# Generated by OpenFakeRAM
VERSION 5.7 ;
BUSBITCHARS "[]" ;
PROPERTYDEFINITIONS
  MACRO width INTEGER ;
  MACRO depth INTEGER ;
  MACRO banks INTEGER ;
END PROPERTYDEFINITIONS
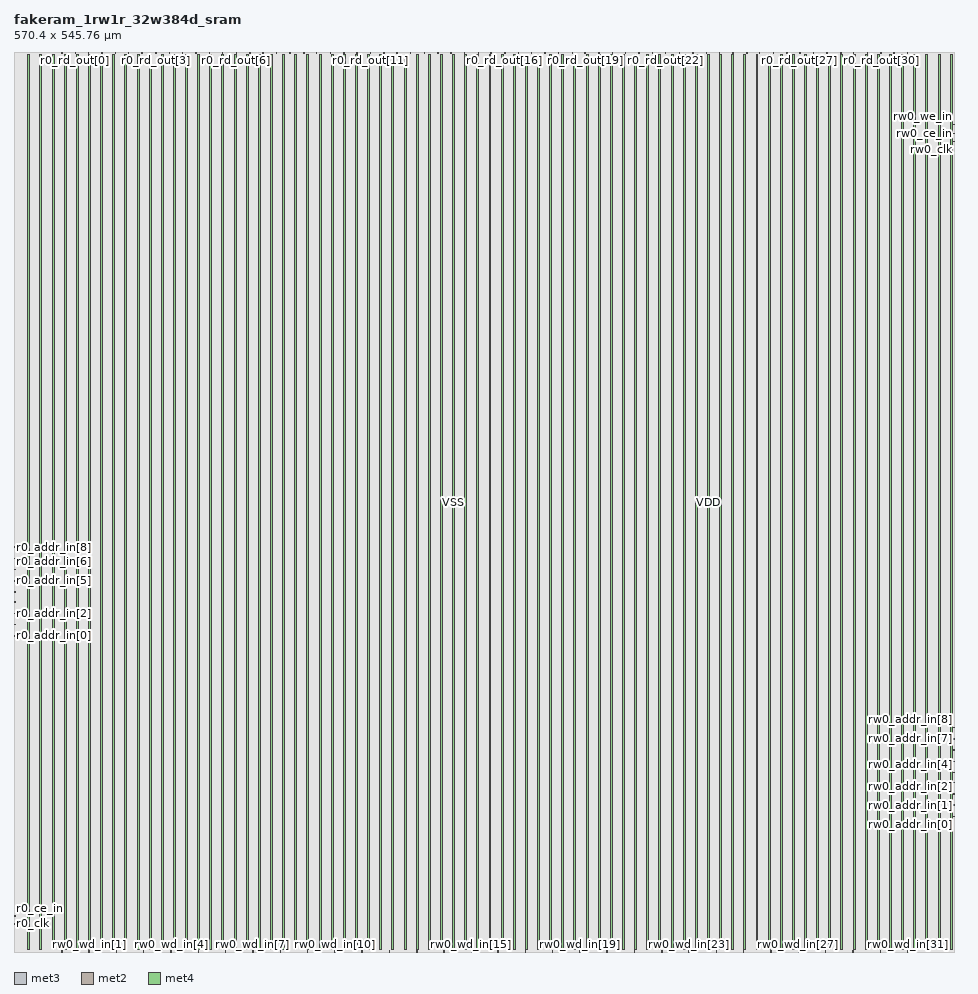
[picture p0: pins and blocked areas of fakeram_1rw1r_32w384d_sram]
MACRO fakeram_1rw1r_32w384d_sram
  PROPERTY width 32 ;
  PROPERTY depth 384 ;
  PROPERTY banks 1 ;
  FOREIGN fakeram_1rw1r_32w384d_sram 0 0 ;
  SYMMETRY X Y R90 ;
  SIZE 570.400 BY 545.760 ;
  CLASS BLOCK ;
  PIN r0_clk
    DIRECTION INPUT ;
    USE SIGNAL ;
    SHAPE ABUTMENT ;
    PORT
      LAYER met3 ;
      RECT 0.000 16.850 0.800 17.150 ;
    END
  END r0_clk
  PIN r0_ce_in
    DIRECTION INPUT ;
    USE SIGNAL ;
    SHAPE ABUTMENT ;
    PORT
      LAYER met3 ;
      RECT 0.000 21.610 0.800 21.910 ;
    END
  END r0_ce_in
  PIN r0_addr_in[0]
    DIRECTION INPUT ;
    USE SIGNAL ;
    SHAPE ABUTMENT ;
    PORT
      LAYER met3 ;
      RECT 0.000 191.610 0.800 191.910 ;
    END
  END r0_addr_in[0]
  PIN r0_addr_in[1]
    DIRECTION INPUT ;
    USE SIGNAL ;
    SHAPE ABUTMENT ;
    PORT
      LAYER met3 ;
      RECT 0.000 198.410 0.800 198.710 ;
    END
  END r0_addr_in[1]
  PIN r0_addr_in[2]
    DIRECTION INPUT ;
    USE SIGNAL ;
    SHAPE ABUTMENT ;
    PORT
      LAYER met3 ;
      RECT 0.000 205.210 0.800 205.510 ;
    END
  END r0_addr_in[2]
  PIN r0_addr_in[3]
    DIRECTION INPUT ;
    USE SIGNAL ;
    SHAPE ABUTMENT ;
    PORT
      LAYER met3 ;
      RECT 0.000 212.010 0.800 212.310 ;
    END
  END r0_addr_in[3]
  PIN r0_addr_in[4]
    DIRECTION INPUT ;
    USE SIGNAL ;
    SHAPE ABUTMENT ;
    PORT
      LAYER met3 ;
      RECT 0.000 218.130 0.800 218.430 ;
    END
  END r0_addr_in[4]
  PIN r0_addr_in[5]
    DIRECTION INPUT ;
    USE SIGNAL ;
    SHAPE ABUTMENT ;
    PORT
      LAYER met3 ;
      RECT 0.000 224.930 0.800 225.230 ;
    END
  END r0_addr_in[5]
  PIN r0_addr_in[6]
    DIRECTION INPUT ;
    USE SIGNAL ;
    SHAPE ABUTMENT ;
    PORT
      LAYER met3 ;
      RECT 0.000 231.730 0.800 232.030 ;
    END
  END r0_addr_in[6]
  PIN r0_addr_in[7]
    DIRECTION INPUT ;
    USE SIGNAL ;
    SHAPE ABUTMENT ;
    PORT
      LAYER met3 ;
      RECT 0.000 238.530 0.800 238.830 ;
    END
  END r0_addr_in[7]
  PIN r0_addr_in[8]
    DIRECTION INPUT ;
    USE SIGNAL ;
    SHAPE ABUTMENT ;
    PORT
      LAYER met3 ;
      RECT 0.000 245.330 0.800 245.630 ;
    END
  END r0_addr_in[8]
  PIN rw0_rd_out[0]
    DIRECTION OUTPUT ;
    USE SIGNAL ;
    SHAPE ABUTMENT ;
    PORT
      LAYER met2 ;
      RECT 28.830 544.960 29.130 545.760 ;
    END
  END rw0_rd_out[0]
  PIN r0_rd_out[0]
    DIRECTION OUTPUT ;
    USE SIGNAL ;
    SHAPE ABUTMENT ;
    PORT
      LAYER met2 ;
      RECT 37.110 544.960 37.410 545.760 ;
    END
  END r0_rd_out[0]
  PIN rw0_rd_out[1]
    DIRECTION OUTPUT ;
    USE SIGNAL ;
    SHAPE ABUTMENT ;
    PORT
      LAYER met2 ;
      RECT 44.930 544.960 45.230 545.760 ;
    END
  END rw0_rd_out[1]
  PIN r0_rd_out[1]
    DIRECTION OUTPUT ;
    USE SIGNAL ;
    SHAPE ABUTMENT ;
    PORT
      LAYER met2 ;
      RECT 53.210 544.960 53.510 545.760 ;
    END
  END r0_rd_out[1]
  PIN rw0_rd_out[2]
    DIRECTION OUTPUT ;
    USE SIGNAL ;
    SHAPE ABUTMENT ;
    PORT
      LAYER met2 ;
      RECT 61.490 544.960 61.790 545.760 ;
    END
  END rw0_rd_out[2]
  PIN r0_rd_out[2]
    DIRECTION OUTPUT ;
    USE SIGNAL ;
    SHAPE ABUTMENT ;
    PORT
      LAYER met2 ;
      RECT 69.310 544.960 69.610 545.760 ;
    END
  END r0_rd_out[2]
  PIN rw0_rd_out[3]
    DIRECTION OUTPUT ;
    USE SIGNAL ;
    SHAPE ABUTMENT ;
    PORT
      LAYER met2 ;
      RECT 77.590 544.960 77.890 545.760 ;
    END
  END rw0_rd_out[3]
  PIN r0_rd_out[3]
    DIRECTION OUTPUT ;
    USE SIGNAL ;
    SHAPE ABUTMENT ;
    PORT
      LAYER met2 ;
      RECT 85.870 544.960 86.170 545.760 ;
    END
  END r0_rd_out[3]
  PIN rw0_rd_out[4]
    DIRECTION OUTPUT ;
    USE SIGNAL ;
    SHAPE ABUTMENT ;
    PORT
      LAYER met2 ;
      RECT 94.150 544.960 94.450 545.760 ;
    END
  END rw0_rd_out[4]
  PIN r0_rd_out[4]
    DIRECTION OUTPUT ;
    USE SIGNAL ;
    SHAPE ABUTMENT ;
    PORT
      LAYER met2 ;
      RECT 101.970 544.960 102.270 545.760 ;
    END
  END r0_rd_out[4]
  PIN rw0_rd_out[5]
    DIRECTION OUTPUT ;
    USE SIGNAL ;
    SHAPE ABUTMENT ;
    PORT
      LAYER met2 ;
      RECT 110.250 544.960 110.550 545.760 ;
    END
  END rw0_rd_out[5]
  PIN r0_rd_out[5]
    DIRECTION OUTPUT ;
    USE SIGNAL ;
    SHAPE ABUTMENT ;
    PORT
      LAYER met2 ;
      RECT 118.530 544.960 118.830 545.760 ;
    END
  END r0_rd_out[5]
  PIN rw0_rd_out[6]
    DIRECTION OUTPUT ;
    USE SIGNAL ;
    SHAPE ABUTMENT ;
    PORT
      LAYER met2 ;
      RECT 126.350 544.960 126.650 545.760 ;
    END
  END rw0_rd_out[6]
  PIN r0_rd_out[6]
    DIRECTION OUTPUT ;
    USE SIGNAL ;
    SHAPE ABUTMENT ;
    PORT
      LAYER met2 ;
      RECT 134.630 544.960 134.930 545.760 ;
    END
  END r0_rd_out[6]
  PIN rw0_rd_out[7]
    DIRECTION OUTPUT ;
    USE SIGNAL ;
    SHAPE ABUTMENT ;
    PORT
      LAYER met2 ;
      RECT 142.910 544.960 143.210 545.760 ;
    END
  END rw0_rd_out[7]
  PIN r0_rd_out[7]
    DIRECTION OUTPUT ;
    USE SIGNAL ;
    SHAPE ABUTMENT ;
    PORT
      LAYER met2 ;
      RECT 150.730 544.960 151.030 545.760 ;
    END
  END r0_rd_out[7]
  PIN rw0_rd_out[8]
    DIRECTION OUTPUT ;
    USE SIGNAL ;
    SHAPE ABUTMENT ;
    PORT
      LAYER met2 ;
      RECT 159.010 544.960 159.310 545.760 ;
    END
  END rw0_rd_out[8]
  PIN r0_rd_out[8]
    DIRECTION OUTPUT ;
    USE SIGNAL ;
    SHAPE ABUTMENT ;
    PORT
      LAYER met2 ;
      RECT 167.290 544.960 167.590 545.760 ;
    END
  END r0_rd_out[8]
  PIN rw0_rd_out[9]
    DIRECTION OUTPUT ;
    USE SIGNAL ;
    SHAPE ABUTMENT ;
    PORT
      LAYER met2 ;
      RECT 175.570 544.960 175.870 545.760 ;
    END
  END rw0_rd_out[9]
  PIN r0_rd_out[9]
    DIRECTION OUTPUT ;
    USE SIGNAL ;
    SHAPE ABUTMENT ;
    PORT
      LAYER met2 ;
      RECT 183.390 544.960 183.690 545.760 ;
    END
  END r0_rd_out[9]
  PIN rw0_rd_out[10]
    DIRECTION OUTPUT ;
    USE SIGNAL ;
    SHAPE ABUTMENT ;
    PORT
      LAYER met2 ;
      RECT 191.670 544.960 191.970 545.760 ;
    END
  END rw0_rd_out[10]
  PIN r0_rd_out[10]
    DIRECTION OUTPUT ;
    USE SIGNAL ;
    SHAPE ABUTMENT ;
    PORT
      LAYER met2 ;
      RECT 199.950 544.960 200.250 545.760 ;
    END
  END r0_rd_out[10]
  PIN rw0_rd_out[11]
    DIRECTION OUTPUT ;
    USE SIGNAL ;
    SHAPE ABUTMENT ;
    PORT
      LAYER met2 ;
      RECT 207.770 544.960 208.070 545.760 ;
    END
  END rw0_rd_out[11]
  PIN r0_rd_out[11]
    DIRECTION OUTPUT ;
    USE SIGNAL ;
    SHAPE ABUTMENT ;
    PORT
      LAYER met2 ;
      RECT 216.050 544.960 216.350 545.760 ;
    END
  END r0_rd_out[11]
  PIN rw0_rd_out[12]
    DIRECTION OUTPUT ;
    USE SIGNAL ;
    SHAPE ABUTMENT ;
    PORT
      LAYER met2 ;
      RECT 224.330 544.960 224.630 545.760 ;
    END
  END rw0_rd_out[12]
  PIN r0_rd_out[12]
    DIRECTION OUTPUT ;
    USE SIGNAL ;
    SHAPE ABUTMENT ;
    PORT
      LAYER met2 ;
      RECT 232.150 544.960 232.450 545.760 ;
    END
  END r0_rd_out[12]
  PIN rw0_rd_out[13]
    DIRECTION OUTPUT ;
    USE SIGNAL ;
    SHAPE ABUTMENT ;
    PORT
      LAYER met2 ;
      RECT 240.430 544.960 240.730 545.760 ;
    END
  END rw0_rd_out[13]
  PIN r0_rd_out[13]
    DIRECTION OUTPUT ;
    USE SIGNAL ;
    SHAPE ABUTMENT ;
    PORT
      LAYER met2 ;
      RECT 248.710 544.960 249.010 545.760 ;
    END
  END r0_rd_out[13]
  PIN rw0_rd_out[14]
    DIRECTION OUTPUT ;
    USE SIGNAL ;
    SHAPE ABUTMENT ;
    PORT
      LAYER met2 ;
      RECT 256.990 544.960 257.290 545.760 ;
    END
  END rw0_rd_out[14]
  PIN r0_rd_out[14]
    DIRECTION OUTPUT ;
    USE SIGNAL ;
    SHAPE ABUTMENT ;
    PORT
      LAYER met2 ;
      RECT 264.810 544.960 265.110 545.760 ;
    END
  END r0_rd_out[14]
  PIN rw0_rd_out[15]
    DIRECTION OUTPUT ;
    USE SIGNAL ;
    SHAPE ABUTMENT ;
    PORT
      LAYER met2 ;
      RECT 273.090 544.960 273.390 545.760 ;
    END
  END rw0_rd_out[15]
  PIN r0_rd_out[15]
    DIRECTION OUTPUT ;
    USE SIGNAL ;
    SHAPE ABUTMENT ;
    PORT
      LAYER met2 ;
      RECT 281.370 544.960 281.670 545.760 ;
    END
  END r0_rd_out[15]
  PIN rw0_rd_out[16]
    DIRECTION OUTPUT ;
    USE SIGNAL ;
    SHAPE ABUTMENT ;
    PORT
      LAYER met2 ;
      RECT 289.190 544.960 289.490 545.760 ;
    END
  END rw0_rd_out[16]
  PIN r0_rd_out[16]
    DIRECTION OUTPUT ;
    USE SIGNAL ;
    SHAPE ABUTMENT ;
    PORT
      LAYER met2 ;
      RECT 297.470 544.960 297.770 545.760 ;
    END
  END r0_rd_out[16]
  PIN rw0_rd_out[17]
    DIRECTION OUTPUT ;
    USE SIGNAL ;
    SHAPE ABUTMENT ;
    PORT
      LAYER met2 ;
      RECT 305.750 544.960 306.050 545.760 ;
    END
  END rw0_rd_out[17]
  PIN r0_rd_out[17]
    DIRECTION OUTPUT ;
    USE SIGNAL ;
    SHAPE ABUTMENT ;
    PORT
      LAYER met2 ;
      RECT 313.570 544.960 313.870 545.760 ;
    END
  END r0_rd_out[17]
  PIN rw0_rd_out[18]
    DIRECTION OUTPUT ;
    USE SIGNAL ;
    SHAPE ABUTMENT ;
    PORT
      LAYER met2 ;
      RECT 321.850 544.960 322.150 545.760 ;
    END
  END rw0_rd_out[18]
  PIN r0_rd_out[18]
    DIRECTION OUTPUT ;
    USE SIGNAL ;
    SHAPE ABUTMENT ;
    PORT
      LAYER met2 ;
      RECT 330.130 544.960 330.430 545.760 ;
    END
  END r0_rd_out[18]
  PIN rw0_rd_out[19]
    DIRECTION OUTPUT ;
    USE SIGNAL ;
    SHAPE ABUTMENT ;
    PORT
      LAYER met2 ;
      RECT 338.410 544.960 338.710 545.760 ;
    END
  END rw0_rd_out[19]
  PIN r0_rd_out[19]
    DIRECTION OUTPUT ;
    USE SIGNAL ;
    SHAPE ABUTMENT ;
    PORT
      LAYER met2 ;
      RECT 346.230 544.960 346.530 545.760 ;
    END
  END r0_rd_out[19]
  PIN rw0_rd_out[20]
    DIRECTION OUTPUT ;
    USE SIGNAL ;
    SHAPE ABUTMENT ;
    PORT
      LAYER met2 ;
      RECT 354.510 544.960 354.810 545.760 ;
    END
  END rw0_rd_out[20]
  PIN r0_rd_out[20]
    DIRECTION OUTPUT ;
    USE SIGNAL ;
    SHAPE ABUTMENT ;
    PORT
      LAYER met2 ;
      RECT 362.790 544.960 363.090 545.760 ;
    END
  END r0_rd_out[20]
  PIN rw0_rd_out[21]
    DIRECTION OUTPUT ;
    USE SIGNAL ;
    SHAPE ABUTMENT ;
    PORT
      LAYER met2 ;
      RECT 370.610 544.960 370.910 545.760 ;
    END
  END rw0_rd_out[21]
  PIN r0_rd_out[21]
    DIRECTION OUTPUT ;
    USE SIGNAL ;
    SHAPE ABUTMENT ;
    PORT
      LAYER met2 ;
      RECT 378.890 544.960 379.190 545.760 ;
    END
  END r0_rd_out[21]
  PIN rw0_rd_out[22]
    DIRECTION OUTPUT ;
    USE SIGNAL ;
    SHAPE ABUTMENT ;
    PORT
      LAYER met2 ;
      RECT 387.170 544.960 387.470 545.760 ;
    END
  END rw0_rd_out[22]
  PIN r0_rd_out[22]
    DIRECTION OUTPUT ;
    USE SIGNAL ;
    SHAPE ABUTMENT ;
    PORT
      LAYER met2 ;
      RECT 394.990 544.960 395.290 545.760 ;
    END
  END r0_rd_out[22]
  PIN rw0_rd_out[23]
    DIRECTION OUTPUT ;
    USE SIGNAL ;
    SHAPE ABUTMENT ;
    PORT
      LAYER met2 ;
      RECT 403.270 544.960 403.570 545.760 ;
    END
  END rw0_rd_out[23]
  PIN r0_rd_out[23]
    DIRECTION OUTPUT ;
    USE SIGNAL ;
    SHAPE ABUTMENT ;
    PORT
      LAYER met2 ;
      RECT 411.550 544.960 411.850 545.760 ;
    END
  END r0_rd_out[23]
  PIN rw0_rd_out[24]
    DIRECTION OUTPUT ;
    USE SIGNAL ;
    SHAPE ABUTMENT ;
    PORT
      LAYER met2 ;
      RECT 419.830 544.960 420.130 545.760 ;
    END
  END rw0_rd_out[24]
  PIN r0_rd_out[24]
    DIRECTION OUTPUT ;
    USE SIGNAL ;
    SHAPE ABUTMENT ;
    PORT
      LAYER met2 ;
      RECT 427.650 544.960 427.950 545.760 ;
    END
  END r0_rd_out[24]
  PIN rw0_rd_out[25]
    DIRECTION OUTPUT ;
    USE SIGNAL ;
    SHAPE ABUTMENT ;
    PORT
      LAYER met2 ;
      RECT 435.930 544.960 436.230 545.760 ;
    END
  END rw0_rd_out[25]
  PIN r0_rd_out[25]
    DIRECTION OUTPUT ;
    USE SIGNAL ;
    SHAPE ABUTMENT ;
    PORT
      LAYER met2 ;
      RECT 444.210 544.960 444.510 545.760 ;
    END
  END r0_rd_out[25]
  PIN rw0_rd_out[26]
    DIRECTION OUTPUT ;
    USE SIGNAL ;
    SHAPE ABUTMENT ;
    PORT
      LAYER met2 ;
      RECT 452.030 544.960 452.330 545.760 ;
    END
  END rw0_rd_out[26]
  PIN r0_rd_out[26]
    DIRECTION OUTPUT ;
    USE SIGNAL ;
    SHAPE ABUTMENT ;
    PORT
      LAYER met2 ;
      RECT 460.310 544.960 460.610 545.760 ;
    END
  END r0_rd_out[26]
  PIN rw0_rd_out[27]
    DIRECTION OUTPUT ;
    USE SIGNAL ;
    SHAPE ABUTMENT ;
    PORT
      LAYER met2 ;
      RECT 468.590 544.960 468.890 545.760 ;
    END
  END rw0_rd_out[27]
  PIN r0_rd_out[27]
    DIRECTION OUTPUT ;
    USE SIGNAL ;
    SHAPE ABUTMENT ;
    PORT
      LAYER met2 ;
      RECT 476.410 544.960 476.710 545.760 ;
    END
  END r0_rd_out[27]
  PIN rw0_rd_out[28]
    DIRECTION OUTPUT ;
    USE SIGNAL ;
    SHAPE ABUTMENT ;
    PORT
      LAYER met2 ;
      RECT 484.690 544.960 484.990 545.760 ;
    END
  END rw0_rd_out[28]
  PIN r0_rd_out[28]
    DIRECTION OUTPUT ;
    USE SIGNAL ;
    SHAPE ABUTMENT ;
    PORT
      LAYER met2 ;
      RECT 492.970 544.960 493.270 545.760 ;
    END
  END r0_rd_out[28]
  PIN rw0_rd_out[29]
    DIRECTION OUTPUT ;
    USE SIGNAL ;
    SHAPE ABUTMENT ;
    PORT
      LAYER met2 ;
      RECT 501.250 544.960 501.550 545.760 ;
    END
  END rw0_rd_out[29]
  PIN r0_rd_out[29]
    DIRECTION OUTPUT ;
    USE SIGNAL ;
    SHAPE ABUTMENT ;
    PORT
      LAYER met2 ;
      RECT 509.070 544.960 509.370 545.760 ;
    END
  END r0_rd_out[29]
  PIN rw0_rd_out[30]
    DIRECTION OUTPUT ;
    USE SIGNAL ;
    SHAPE ABUTMENT ;
    PORT
      LAYER met2 ;
      RECT 517.350 544.960 517.650 545.760 ;
    END
  END rw0_rd_out[30]
  PIN r0_rd_out[30]
    DIRECTION OUTPUT ;
    USE SIGNAL ;
    SHAPE ABUTMENT ;
    PORT
      LAYER met2 ;
      RECT 525.630 544.960 525.930 545.760 ;
    END
  END r0_rd_out[30]
  PIN rw0_rd_out[31]
    DIRECTION OUTPUT ;
    USE SIGNAL ;
    SHAPE ABUTMENT ;
    PORT
      LAYER met2 ;
      RECT 533.450 544.960 533.750 545.760 ;
    END
  END rw0_rd_out[31]
  PIN r0_rd_out[31]
    DIRECTION OUTPUT ;
    USE SIGNAL ;
    SHAPE ABUTMENT ;
    PORT
      LAYER met2 ;
      RECT 541.730 544.960 542.030 545.760 ;
    END
  END r0_rd_out[31]
  PIN rw0_clk
    DIRECTION INPUT ;
    USE SIGNAL ;
    SHAPE ABUTMENT ;
    PORT
      LAYER met3 ;
      RECT 569.600 491.490 570.400 491.790 ;
    END
  END rw0_clk
  PIN rw0_ce_in
    DIRECTION INPUT ;
    USE SIGNAL ;
    SHAPE ABUTMENT ;
    PORT
      LAYER met3 ;
      RECT 569.600 496.250 570.400 496.550 ;
    END
  END rw0_ce_in
  PIN rw0_we_in
    DIRECTION INPUT ;
    USE SIGNAL ;
    SHAPE ABUTMENT ;
    PORT
      LAYER met3 ;
      RECT 569.600 501.690 570.400 501.990 ;
    END
  END rw0_we_in
  PIN rw0_addr_in[0]
    DIRECTION INPUT ;
    USE SIGNAL ;
    SHAPE ABUTMENT ;
    PORT
      LAYER met3 ;
      RECT 569.600 82.130 570.400 82.430 ;
    END
  END rw0_addr_in[0]
  PIN rw0_addr_in[1]
    DIRECTION INPUT ;
    USE SIGNAL ;
    SHAPE ABUTMENT ;
    PORT
      LAYER met3 ;
      RECT 569.600 88.930 570.400 89.230 ;
    END
  END rw0_addr_in[1]
  PIN rw0_addr_in[2]
    DIRECTION INPUT ;
    USE SIGNAL ;
    SHAPE ABUTMENT ;
    PORT
      LAYER met3 ;
      RECT 569.600 95.730 570.400 96.030 ;
    END
  END rw0_addr_in[2]
  PIN rw0_addr_in[3]
    DIRECTION INPUT ;
    USE SIGNAL ;
    SHAPE ABUTMENT ;
    PORT
      LAYER met3 ;
      RECT 569.600 102.530 570.400 102.830 ;
    END
  END rw0_addr_in[3]
  PIN rw0_addr_in[4]
    DIRECTION INPUT ;
    USE SIGNAL ;
    SHAPE ABUTMENT ;
    PORT
      LAYER met3 ;
      RECT 569.600 108.650 570.400 108.950 ;
    END
  END rw0_addr_in[4]
  PIN rw0_addr_in[5]
    DIRECTION INPUT ;
    USE SIGNAL ;
    SHAPE ABUTMENT ;
    PORT
      LAYER met3 ;
      RECT 569.600 115.450 570.400 115.750 ;
    END
  END rw0_addr_in[5]
  PIN rw0_addr_in[6]
    DIRECTION INPUT ;
    USE SIGNAL ;
    SHAPE ABUTMENT ;
    PORT
      LAYER met3 ;
      RECT 569.600 122.250 570.400 122.550 ;
    END
  END rw0_addr_in[6]
  PIN rw0_addr_in[7]
    DIRECTION INPUT ;
    USE SIGNAL ;
    SHAPE ABUTMENT ;
    PORT
      LAYER met3 ;
      RECT 569.600 129.050 570.400 129.350 ;
    END
  END rw0_addr_in[7]
  PIN rw0_addr_in[8]
    DIRECTION INPUT ;
    USE SIGNAL ;
    SHAPE ABUTMENT ;
    PORT
      LAYER met3 ;
      RECT 569.600 135.850 570.400 136.150 ;
    END
  END rw0_addr_in[8]
  PIN rw0_wd_in[0]
    DIRECTION INPUT ;
    USE SIGNAL ;
    SHAPE ABUTMENT ;
    PORT
      LAYER met2 ;
      RECT 28.830 0.000 29.130 0.800 ;
    END
  END rw0_wd_in[0]
  PIN rw0_wd_in[1]
    DIRECTION INPUT ;
    USE SIGNAL ;
    SHAPE ABUTMENT ;
    PORT
      LAYER met2 ;
      RECT 45.390 0.000 45.690 0.800 ;
    END
  END rw0_wd_in[1]
  PIN rw0_wd_in[2]
    DIRECTION INPUT ;
    USE SIGNAL ;
    SHAPE ABUTMENT ;
    PORT
      LAYER met2 ;
      RECT 61.950 0.000 62.250 0.800 ;
    END
  END rw0_wd_in[2]
  PIN rw0_wd_in[3]
    DIRECTION INPUT ;
    USE SIGNAL ;
    SHAPE ABUTMENT ;
    PORT
      LAYER met2 ;
      RECT 78.510 0.000 78.810 0.800 ;
    END
  END rw0_wd_in[3]
  PIN rw0_wd_in[4]
    DIRECTION INPUT ;
    USE SIGNAL ;
    SHAPE ABUTMENT ;
    PORT
      LAYER met2 ;
      RECT 95.070 0.000 95.370 0.800 ;
    END
  END rw0_wd_in[4]
  PIN rw0_wd_in[5]
    DIRECTION INPUT ;
    USE SIGNAL ;
    SHAPE ABUTMENT ;
    PORT
      LAYER met2 ;
      RECT 111.630 0.000 111.930 0.800 ;
    END
  END rw0_wd_in[5]
  PIN rw0_wd_in[6]
    DIRECTION INPUT ;
    USE SIGNAL ;
    SHAPE ABUTMENT ;
    PORT
      LAYER met2 ;
      RECT 128.190 0.000 128.490 0.800 ;
    END
  END rw0_wd_in[6]
  PIN rw0_wd_in[7]
    DIRECTION INPUT ;
    USE SIGNAL ;
    SHAPE ABUTMENT ;
    PORT
      LAYER met2 ;
      RECT 144.750 0.000 145.050 0.800 ;
    END
  END rw0_wd_in[7]
  PIN rw0_wd_in[8]
    DIRECTION INPUT ;
    USE SIGNAL ;
    SHAPE ABUTMENT ;
    PORT
      LAYER met2 ;
      RECT 161.310 0.000 161.610 0.800 ;
    END
  END rw0_wd_in[8]
  PIN rw0_wd_in[9]
    DIRECTION INPUT ;
    USE SIGNAL ;
    SHAPE ABUTMENT ;
    PORT
      LAYER met2 ;
      RECT 177.870 0.000 178.170 0.800 ;
    END
  END rw0_wd_in[9]
  PIN rw0_wd_in[10]
    DIRECTION INPUT ;
    USE SIGNAL ;
    SHAPE ABUTMENT ;
    PORT
      LAYER met2 ;
      RECT 194.430 0.000 194.730 0.800 ;
    END
  END rw0_wd_in[10]
  PIN rw0_wd_in[11]
    DIRECTION INPUT ;
    USE SIGNAL ;
    SHAPE ABUTMENT ;
    PORT
      LAYER met2 ;
      RECT 210.990 0.000 211.290 0.800 ;
    END
  END rw0_wd_in[11]
  PIN rw0_wd_in[12]
    DIRECTION INPUT ;
    USE SIGNAL ;
    SHAPE ABUTMENT ;
    PORT
      LAYER met2 ;
      RECT 227.550 0.000 227.850 0.800 ;
    END
  END rw0_wd_in[12]
  PIN rw0_wd_in[13]
    DIRECTION INPUT ;
    USE SIGNAL ;
    SHAPE ABUTMENT ;
    PORT
      LAYER met2 ;
      RECT 244.110 0.000 244.410 0.800 ;
    END
  END rw0_wd_in[13]
  PIN rw0_wd_in[14]
    DIRECTION INPUT ;
    USE SIGNAL ;
    SHAPE ABUTMENT ;
    PORT
      LAYER met2 ;
      RECT 260.670 0.000 260.970 0.800 ;
    END
  END rw0_wd_in[14]
  PIN rw0_wd_in[15]
    DIRECTION INPUT ;
    USE SIGNAL ;
    SHAPE ABUTMENT ;
    PORT
      LAYER met2 ;
      RECT 277.230 0.000 277.530 0.800 ;
    END
  END rw0_wd_in[15]
  PIN rw0_wd_in[16]
    DIRECTION INPUT ;
    USE SIGNAL ;
    SHAPE ABUTMENT ;
    PORT
      LAYER met2 ;
      RECT 293.330 0.000 293.630 0.800 ;
    END
  END rw0_wd_in[16]
  PIN rw0_wd_in[17]
    DIRECTION INPUT ;
    USE SIGNAL ;
    SHAPE ABUTMENT ;
    PORT
      LAYER met2 ;
      RECT 309.890 0.000 310.190 0.800 ;
    END
  END rw0_wd_in[17]
  PIN rw0_wd_in[18]
    DIRECTION INPUT ;
    USE SIGNAL ;
    SHAPE ABUTMENT ;
    PORT
      LAYER met2 ;
      RECT 326.450 0.000 326.750 0.800 ;
    END
  END rw0_wd_in[18]
  PIN rw0_wd_in[19]
    DIRECTION INPUT ;
    USE SIGNAL ;
    SHAPE ABUTMENT ;
    PORT
      LAYER met2 ;
      RECT 343.010 0.000 343.310 0.800 ;
    END
  END rw0_wd_in[19]
  PIN rw0_wd_in[20]
    DIRECTION INPUT ;
    USE SIGNAL ;
    SHAPE ABUTMENT ;
    PORT
      LAYER met2 ;
      RECT 359.570 0.000 359.870 0.800 ;
    END
  END rw0_wd_in[20]
  PIN rw0_wd_in[21]
    DIRECTION INPUT ;
    USE SIGNAL ;
    SHAPE ABUTMENT ;
    PORT
      LAYER met2 ;
      RECT 376.130 0.000 376.430 0.800 ;
    END
  END rw0_wd_in[21]
  PIN rw0_wd_in[22]
    DIRECTION INPUT ;
    USE SIGNAL ;
    SHAPE ABUTMENT ;
    PORT
      LAYER met2 ;
      RECT 392.690 0.000 392.990 0.800 ;
    END
  END rw0_wd_in[22]
  PIN rw0_wd_in[23]
    DIRECTION INPUT ;
    USE SIGNAL ;
    SHAPE ABUTMENT ;
    PORT
      LAYER met2 ;
      RECT 409.250 0.000 409.550 0.800 ;
    END
  END rw0_wd_in[23]
  PIN rw0_wd_in[24]
    DIRECTION INPUT ;
    USE SIGNAL ;
    SHAPE ABUTMENT ;
    PORT
      LAYER met2 ;
      RECT 425.810 0.000 426.110 0.800 ;
    END
  END rw0_wd_in[24]
  PIN rw0_wd_in[25]
    DIRECTION INPUT ;
    USE SIGNAL ;
    SHAPE ABUTMENT ;
    PORT
      LAYER met2 ;
      RECT 442.370 0.000 442.670 0.800 ;
    END
  END rw0_wd_in[25]
  PIN rw0_wd_in[26]
    DIRECTION INPUT ;
    USE SIGNAL ;
    SHAPE ABUTMENT ;
    PORT
      LAYER met2 ;
      RECT 458.930 0.000 459.230 0.800 ;
    END
  END rw0_wd_in[26]
  PIN rw0_wd_in[27]
    DIRECTION INPUT ;
    USE SIGNAL ;
    SHAPE ABUTMENT ;
    PORT
      LAYER met2 ;
      RECT 475.490 0.000 475.790 0.800 ;
    END
  END rw0_wd_in[27]
  PIN rw0_wd_in[28]
    DIRECTION INPUT ;
    USE SIGNAL ;
    SHAPE ABUTMENT ;
    PORT
      LAYER met2 ;
      RECT 492.050 0.000 492.350 0.800 ;
    END
  END rw0_wd_in[28]
  PIN rw0_wd_in[29]
    DIRECTION INPUT ;
    USE SIGNAL ;
    SHAPE ABUTMENT ;
    PORT
      LAYER met2 ;
      RECT 508.610 0.000 508.910 0.800 ;
    END
  END rw0_wd_in[29]
  PIN rw0_wd_in[30]
    DIRECTION INPUT ;
    USE SIGNAL ;
    SHAPE ABUTMENT ;
    PORT
      LAYER met2 ;
      RECT 525.170 0.000 525.470 0.800 ;
    END
  END rw0_wd_in[30]
  PIN rw0_wd_in[31]
    DIRECTION INPUT ;
    USE SIGNAL ;
    SHAPE ABUTMENT ;
    PORT
      LAYER met2 ;
      RECT 541.730 0.000 542.030 0.800 ;
    END
  END rw0_wd_in[31]
  PIN VSS
    DIRECTION INOUT ;
    USE GROUND ;
    PORT
      LAYER met4 ;
      RECT 15.720 1.600 16.920 544.160 ;
      RECT 30.440 1.600 31.640 544.160 ;
      RECT 45.160 1.600 46.360 544.160 ;
      RECT 59.880 1.600 61.080 544.160 ;
      RECT 74.600 1.600 75.800 544.160 ;
      RECT 89.320 1.600 90.520 544.160 ;
      RECT 104.040 1.600 105.240 544.160 ;
      RECT 118.760 1.600 119.960 544.160 ;
      RECT 133.480 1.600 134.680 544.160 ;
      RECT 148.200 1.600 149.400 544.160 ;
      RECT 162.920 1.600 164.120 544.160 ;
      RECT 177.640 1.600 178.840 544.160 ;
      RECT 192.360 1.600 193.560 544.160 ;
      RECT 207.080 1.600 208.280 544.160 ;
      RECT 221.800 1.600 223.000 544.160 ;
      RECT 236.520 1.600 237.720 544.160 ;
      RECT 251.240 1.600 252.440 544.160 ;
      RECT 265.960 1.600 267.160 544.160 ;
      RECT 280.680 1.600 281.880 544.160 ;
      RECT 295.400 1.600 296.600 544.160 ;
      RECT 310.120 1.600 311.320 544.160 ;
      RECT 324.840 1.600 326.040 544.160 ;
      RECT 339.560 1.600 340.760 544.160 ;
      RECT 354.280 1.600 355.480 544.160 ;
      RECT 369.000 1.600 370.200 544.160 ;
      RECT 383.720 1.600 384.920 544.160 ;
      RECT 398.440 1.600 399.640 544.160 ;
      RECT 413.160 1.600 414.360 544.160 ;
      RECT 427.880 1.600 429.080 544.160 ;
      RECT 442.600 1.600 443.800 544.160 ;
      RECT 457.320 1.600 458.520 544.160 ;
      RECT 472.040 1.600 473.240 544.160 ;
      RECT 486.760 1.600 487.960 544.160 ;
      RECT 501.480 1.600 502.680 544.160 ;
      RECT 516.200 1.600 517.400 544.160 ;
      RECT 530.920 1.600 532.120 544.160 ;
      RECT 545.640 1.600 546.840 544.160 ;
      RECT 560.360 1.600 561.560 544.160 ;
    END
  END VSS
  PIN VDD
    DIRECTION INOUT ;
    USE POWER ;
    PORT
      LAYER met4 ;
      RECT 8.360 1.600 9.560 544.160 ;
      RECT 23.080 1.600 24.280 544.160 ;
      RECT 37.800 1.600 39.000 544.160 ;
      RECT 52.520 1.600 53.720 544.160 ;
      RECT 67.240 1.600 68.440 544.160 ;
      RECT 81.960 1.600 83.160 544.160 ;
      RECT 96.680 1.600 97.880 544.160 ;
      RECT 111.400 1.600 112.600 544.160 ;
      RECT 126.120 1.600 127.320 544.160 ;
      RECT 140.840 1.600 142.040 544.160 ;
      RECT 155.560 1.600 156.760 544.160 ;
      RECT 170.280 1.600 171.480 544.160 ;
      RECT 185.000 1.600 186.200 544.160 ;
      RECT 199.720 1.600 200.920 544.160 ;
      RECT 214.440 1.600 215.640 544.160 ;
      RECT 229.160 1.600 230.360 544.160 ;
      RECT 243.880 1.600 245.080 544.160 ;
      RECT 258.600 1.600 259.800 544.160 ;
      RECT 273.320 1.600 274.520 544.160 ;
      RECT 288.040 1.600 289.240 544.160 ;
      RECT 302.760 1.600 303.960 544.160 ;
      RECT 317.480 1.600 318.680 544.160 ;
      RECT 332.200 1.600 333.400 544.160 ;
      RECT 346.920 1.600 348.120 544.160 ;
      RECT 361.640 1.600 362.840 544.160 ;
      RECT 376.360 1.600 377.560 544.160 ;
      RECT 391.080 1.600 392.280 544.160 ;
      RECT 405.800 1.600 407.000 544.160 ;
      RECT 420.520 1.600 421.720 544.160 ;
      RECT 435.240 1.600 436.440 544.160 ;
      RECT 449.960 1.600 451.160 544.160 ;
      RECT 464.680 1.600 465.880 544.160 ;
      RECT 479.400 1.600 480.600 544.160 ;
      RECT 494.120 1.600 495.320 544.160 ;
      RECT 508.840 1.600 510.040 544.160 ;
      RECT 523.560 1.600 524.760 544.160 ;
      RECT 538.280 1.600 539.480 544.160 ;
      RECT 553.000 1.600 554.200 544.160 ;
      RECT 567.720 1.600 568.920 544.160 ;
    END
  END VDD
  OBS
    LAYER met1 ;
    RECT 0 0 570.400 545.760 ;
    LAYER met2 ;
    RECT 0 0 570.400 545.760 ;
    LAYER met3 ;
    RECT 0 0 570.400 545.760 ;
    LAYER met4 ;
    RECT 0 0 570.400 545.760 ;
    LAYER OVERLAP ;
    RECT 0 0 570.400 545.760 ;
  END
END fakeram_1rw1r_32w384d_sram

END LIBRARY
